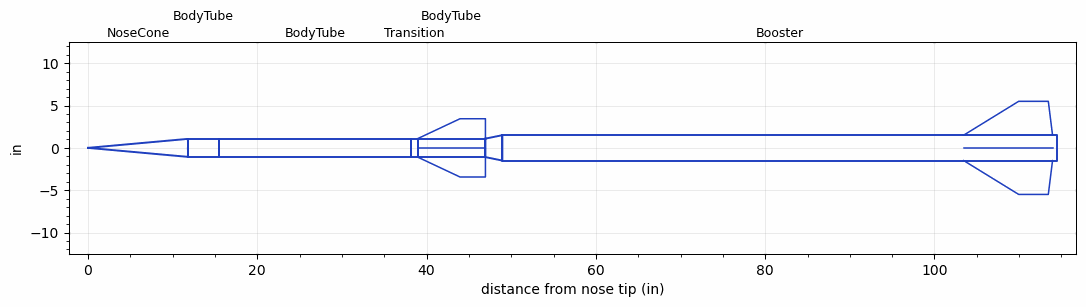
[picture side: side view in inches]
<RASAeroDocument>
 <FileVersion>2</FileVersion>
 <RocketDesign>
  <NoseCone>
   <Length>11.8</Length>
   <Diameter>2.125</Diameter>
   <Shape>Conical</Shape>
   <BluntRadius>0.0651</BluntRadius>
   <Location>0</Location>
  </NoseCone>
  <BodyTube>
   <Length>3.7</Length>
   <Diameter>2.125</Diameter>
   <Location>11.8</Location>
  </BodyTube>
  <BodyTube>
   <Length>22.7</Length>
   <Diameter>2.125</Diameter>
   <Location>15.5</Location>
  </BodyTube>
  <Transition>
   <Length>0.75</Length>
   <Diameter>2.185</Diameter>
   <Location>38.2</Location>
   <RearDiameter>2.185</RearDiameter>
  </Transition>
  <BodyTube>
   <Length>8</Length>
   <Diameter>2.185</Diameter>
   <Location>38.95</Location>
   <Fin>
    <Count>4</Count>
    <Chord>8</Chord>
    <Span>2.35</Span>
    <SweepDistance>5</SweepDistance>
    <TipChord>3</TipChord>
    <Thickness>0.08</Thickness>
    <LERadius>0.01</LERadius>
    <Location>8</Location>
    <AirfoilSection>Double Wedge</AirfoilSection>
    <FX1>1.5</FX1>
    <FX3>0.75</FX3>
   </Fin>
  </BodyTube>
  <Booster>
   <Length>65.5</Length>
   <Diameter>3</Diameter>
   <InsideDiameter>2.185</InsideDiameter>
   <Location>46.95</Location>
   <ShoulderLength>2</ShoulderLength>
   <Fin>
    <Count>4</Count>
    <Chord>10.5</Chord>
    <Span>4</Span>
    <SweepDistance>6.5</SweepDistance>
    <TipChord>3.5</TipChord>
    <Thickness>0.25</Thickness>
    <LERadius>0.02</LERadius>
    <Location>11</Location>
    <AirfoilSection>Hexagonal</AirfoilSection>
    <FX1>0.75</FX1>
    <FX3>0.5</FX3>
   </Fin>
  </Booster>
  <Surface>Camouflage Paint</Surface>
  <ModifiedBarrowman>True</ModifiedBarrowman>
  <Turbulence>True</Turbulence>
  <UseBooster1>False</UseBooster1>
  <UseBooster2>False</UseBooster2>
 </RocketDesign>
 <LaunchSite>
  <Altitude>4000</Altitude>
  <Pressure>29.92</Pressure>
  <RodAngle>2</RodAngle>
  <RodLength>10</RodLength>
  <Temperature>75</Temperature>
  <WindSpeed>7</WindSpeed>
 </LaunchSite>
 <Recovery>
  <Altitude1>0</Altitude1>
  <Altitude2>3000</Altitude2>
  <DeviceType1>Parachute</DeviceType1>
  <DeviceType2>Parachute</DeviceType2>
  <Event1>False</Event1>
  <Event2>False</Event2>
  <Size1>4</Size1>
  <Size2>28</Size2>
  <EventType1>Apogee</EventType1>
  <EventType2>Altitude</EventType2>
  <CD1>1</CD1>
  <CD2>1.75</CD2>
 </Recovery>
 <SimulationList>
  <Simulation>
   <SustainerEngine>L1068  (boostybooska)</SustainerEngine>
   <SustainerLaunchWt>7.3</SustainerLaunchWt>
   <SustainerNozzleDiameter>1.905</SustainerNozzleDiameter>
   <SustainerCG>26.1</SustainerCG>
   <SustainerIgnitionDelay>12</SustainerIgnitionDelay>
   <Booster1Engine>N2922  (MYA)</Booster1Engine>
   <Booster1LaunchWt>34</Booster1LaunchWt>
   <Booster1SeparationDelay>0.02</Booster1SeparationDelay>
   <Booster1IgnitionDelay>0</Booster1IgnitionDelay>
   <Booster1CG>70.27</Booster1CG>
   <Booster1NozzleDiameter>3</Booster1NozzleDiameter>
   <IncludeBooster1>True</IncludeBooster1>
   <Booster2Delay>0</Booster2Delay>
   <IncludeBooster2>False</IncludeBooster2>
   <TimetoApogee>148.6901</TimetoApogee>
   <MaxAltitude>314065.5</MaxAltitude>
   <MaxVelocity>5353.132</MaxVelocity>
   <OptimumWt>9.862499</OptimumWt>
   <OptimumMaxAlt>9.862499</OptimumMaxAlt>
  </Simulation>
 </SimulationList>
</RASAeroDocument>
